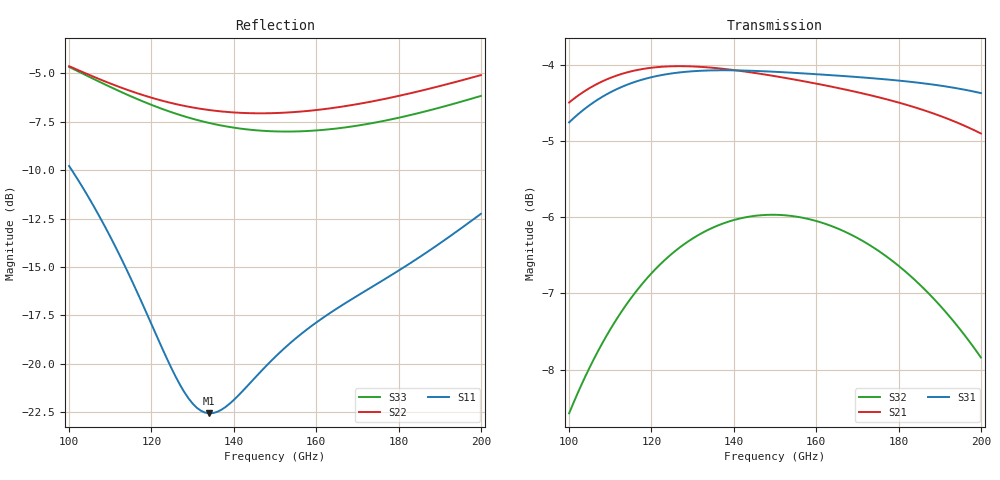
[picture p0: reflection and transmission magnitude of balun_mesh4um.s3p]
! Created with skrf 2.2.0 (http://scikit-rf.org).
# GHz S DB R 50.0
! Port[1] = P1
! Port[2] = P2
! Port[3] = P3
!freq dBS11 angS11 dBS12 angS12 dBS13 angS13
! dBS21 angS21 dBS22 angS22 dBS23 angS23
! dBS31 angS31 dBS32 angS32 dBS33 angS33
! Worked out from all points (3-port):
!   101 points, 100 GHz to 200 GHz, reference 50 ohm
!   strongest paths, dB at 100 GHz, 125 GHz, 150 GHz, 175 GHz, 200 GHz:
!     S31: -4.8, -4.1, -4.1, -4.2, -4.4
!     S21: -4.5, -4.0, -4.1, -4.4, -4.9
!     S32: -8.6, -6.5, -6.0, -6.4, -7.8
!   lowest |S11| = -22.5 dB at 134 GHz (marker M1), VSWR 1.16, Z = 43.2 + j1.51 ohm
!   |S11| at or under -10 dB: 100.6 GHz to end of sweep
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100  -9.79 131.4  -4.49 -15.1  -4.75 160.6
     -4.49 -15.1  -4.64 60.0  -8.58 89.4
     -4.75 160.6  -8.58 89.4  -4.68 48.8
109  -13.03 124.4  -4.19 -29.4  -4.39 145.3
     -4.19 -29.4  -5.45 52.0  -7.56 75.1
     -4.39 145.3  -7.56 75.1  -5.61 39.0
118  -16.99 125.3  -4.05 -42.8  -4.19 131.0
     -4.05 -42.8  -6.14 45.0  -6.86 61.6
     -4.19 131.0  -6.86 61.6  -6.47 30.5
128  -21.46 144.7  -4.02 -56.7  -4.09 116.1
     -4.02 -56.7  -6.69 37.9  -6.35 47.4
     -4.09 116.1  -6.35 47.4  -7.23 22.2
134  -22.55 166.5  -4.03 -64.6  -4.07 107.6
     -4.03 -64.6  -6.90 33.8  -6.16 39.3
     -4.07 107.6  -6.16 39.3  -7.57 17.6
139  -22.05 -177.2  -4.06 -71.0  -4.07 100.8
     -4.06 -71.0  -7.01 30.4  -6.05 32.7
     -4.07 100.8  -6.05 32.7  -7.78 13.9
150  -19.65 -158.8  -4.15 -84.5  -4.09 86.3
     -4.15 -84.5  -7.06 22.5  -5.97 18.8
     -4.09 86.3  -5.97 18.8  -8.00 5.7
173  -16.10 -148.7  -4.40 -111.6  -4.17 57.5
     -4.40 -111.6  -6.48 3.8  -6.37 -8.7
     -4.17 57.5  -6.37 -8.7  -7.60 -12.5
187  -14.22 -146.4  -4.61 -128.1  -4.25 40.0
     -4.61 -128.1  -5.83 -9.1  -6.98 -25.1
     -4.25 40.0  -6.98 -25.1  -6.95 -24.7
200  -12.26 -147.5  -4.90 -143.9  -4.37 23.5
     -4.90 -143.9  -5.10 -22.0  -7.84 -40.4
     -4.37 23.5  -7.84 -40.4  -6.18 -37.0
